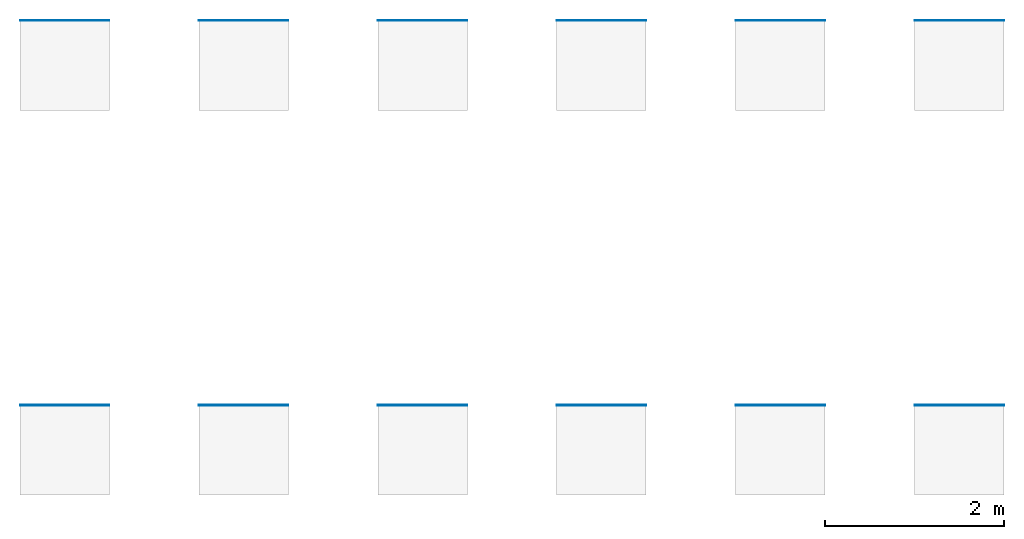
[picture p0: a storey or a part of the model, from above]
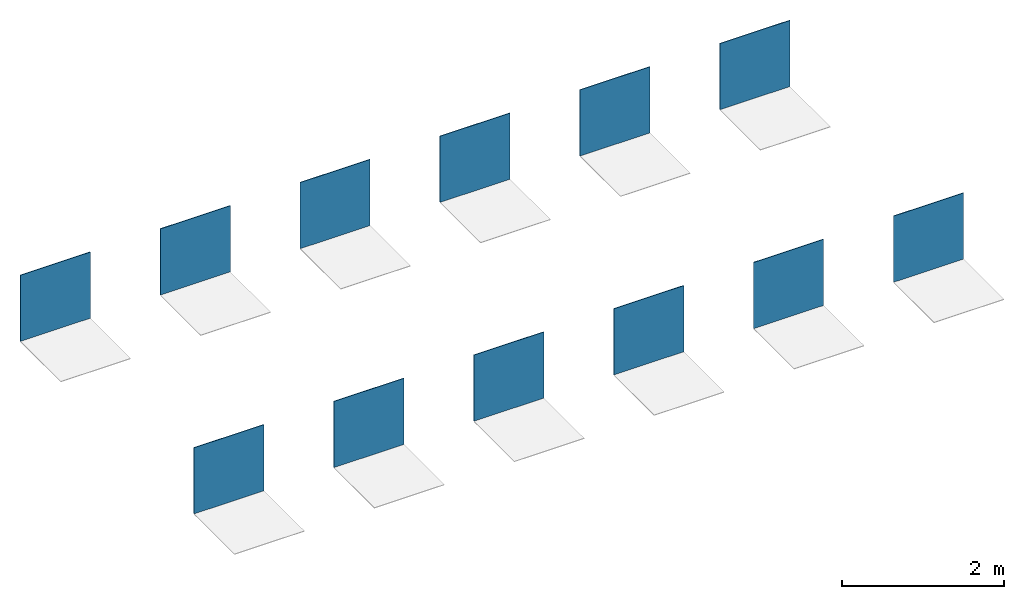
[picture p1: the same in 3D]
Properties of the parts of a building model (IFC2X3), part 1 of 2

# File
Description: ViewDefinition [CoordinationView_V2.0]
Time: 2025-06-20T14:48:58
Written by: The EXPRESS Data Manager Version 5.02.0100.07 : 28 Aug 2013
Made in: 21.1.90.15 - Exporter 21.1.90.15 - Alternate UI 21.1.90.15
Comment: STEP Physical File produced by: The EXPRESS Data Manager Version 5.02.0100.07 : 28 Aug 2013 * Module: EDMstepFileFactory/EDMstandAlone * Creation date: Fri Jun 20 14:48:58 2025 * Host: STB002 * Database: C:\Users\LARISS~1\AppData\Local\Temp\234e31d9-e186-458c-9206-d387dea7a233\5ca75167-f6cb-4baf-9861-9e8454f58231\ifc * Database version: 5507 * Database creation date: Fri Jun 20 14:48:57 2025 * Schema: IFC2X3 * Model: DataRepository.ifc * Model creation date: Fri Jun 20 14:48:57 2025 * Header model: DataRepository.ifc_HeaderModel * Header model creation date: Fri Jun 20 14:48:57 2025 * EDMuser: sdai-user * EDMgroup: sdai-group * License ID and type: 5605 : Permanent license. Expiry date: * EDMstepFileFactory options: 020000

# IfcSite, Default
RefLatitude: 42, 24, 53, 508911; RefLongitude: -71, -15, -29, -58837; RefElevation: 0 mm
Pset_ProductRequirements - Category: Project Information

# IfcBuilding
Pset_BuildingCommon - NumberOfStoreys: 1
Pset_ProductRequirements - Category: Project Information

# IfcBuildingStorey: Level:Level 1, Level 1
LongName: Level 1; Elevation: 0 mm
Pset_AirSideSystemInformation - Name: Level 1
Pset_ProductRequirements - Name: Level 1; Category: Levels

# IfcCovering: Floor:REVIGRÉS-OMNISTONE-HEXAGON-60X60-MATTRECT-BONE, Floor:REVIGRÉS-OMNISTONE-HEXAGON-60X60-MATTRECT-BONE:154203
In: Level 1
Type - PredefinedType: CLADDING; Material: REVIGRÉS-OMNISTONE-HEXAGON-60x60-MATTRECT-BONE 9.8 mm
Type - Pset_CoveringCommon - Reference: 332B13V191; Material: Grés porcelânico
Type - Pset_ElementShading - Roughness: 304.8 mm
Type - Pset_ManufacturerTypeInformation - Manufacturer: REVIGRÉS
Type - Pset_ProductRequirements - Category: Floors
Type - Pset_QuantityTakeOff - Reference: 332B13V191
Type - IFC.REVIGRÉS-Dados do fabricante-Floor Covering - FabricanteURL: https://www.revigres.pt/; ReferenciaModelo: Omnistone; NumeroGlobalDeItemComercial: 332B13V191; Acabamento: MATT RECT; Material: Grés porcelânico; IdentificadorDoOperadorEconomico: 501840856; UrlFabricanteArtigo: https://www.revigres.pt/colecoes/omnistone; PaisOrigem: Portugal
Type - IFC.REVIGRÉS-Dados de desempenho-Floor Covering - Rectilinearidade: ± 0.2% máx.± 0.8 mm; Ortogonalidade: ± 0.2% máx.± 1.5 mm; PlanaridadeDaSuperficie: ± 0.3% máx. ± 1.8 mm; QualidadeDaSuperficie: Cumpre; AbsorcaoDeAgua: < 0.05%; ModuloDeRuptura: > 45 N/mm130; ResistenciaAFlexao: ≥ 3500 N; ResistenciaAAbrasaoProfunda: < 120 mm131; DilatacaoTermicaLinear: ≤ 8,0x10-6 °C-1; ResistenciaAoChoqueTermico: Resiste; DurabilidadeResistenciaAoGeloDegelo: Resiste; ResistenciaAoEscorregamentoDIN51130: R10; ResistenciaAoEscorregamentoDIN51097: B; ResistenciaAoEscorregamentoENV51097: B; ResistenciaAoEscorregamentoENV12633: Class 2; ResistenciaAoEscorregamentoBS7976: >36; ResistenciaAoEscorregamentoANSIA1371: ≥0,42; ResistenciaAoDeslizamentoENV12633: Class 2; ResistenciaAoDeslizamentoBS7976: >36; ResistenciaAsManchas: Class 5; ResistenciaABaixasConcentracoesDeAcidosEAlcalis: Classe LA; ResistenciaAAltasConcentracoesDeAcidosEAlcalis: Classe HA; LibertacaoDeCadmio: 0; LibertacaoDeChumbo: 0
Type - IFC.REVIGRÉS-Dados de especificação-Floor Covering - VariacaoTonalidade: 3; NivelDeTrafego: 5; EPavimento: Sim; ERevestimento: Sim; EExterno: Sim
Type - IFC.REVIGRÉS-Dados geométricos-Floor Covering - AlturaNominal: 9.8 mm; ComprimentoNominal: 59.2 mm; LarguraNominal: 59.2 mm
Type - IFC.REVIGRÉS-Dados de sustentabilidade-Floor Covering - ItemEParcialmenteReciclado: 0; EnergiaTermicaExportada: 0; ItemENovo: Sim; ItemEReciclado: Não; VidaÚtilEsperada: 50; SubstanciasPerigosas: Não; PotencialDeEsgotamentoAbioticoDosRecursosNaoFosseisMineraisEMetais: 0.000701; PotencialDeAquecimentoGlobalBiogenico: -0.48; CombustiveisFosseisComPotencialDeAquecimentoGlobal: 13.9; PotencialDeAquecimentoGlobalUsoDoSoloEMudancaDeUsoDoSolo: 0.0246; PotencialDeEutrofizacaoFraccaoDeNutrientesQueAtingemOCompartimentoFinalDeAguaDoce: 0.000189; PotencialDeEutrofizacaoFraccaoDeNutrientesQueAtingemOCompartimentoFinalMarinho: 0.0122; EnergiaRecuperada: 0.00739; ConsumoDeAguaDoce: 0.113; UtilizacaoLiquidaDeAguaDoce: 0.113; ResiduosPerigososEliminados: 0.00221; ResiduosNaoPerigososEliminados: 1.83; MassaTotalDeResiduosRadioactivosEliminados: 0.000394; EnergiaElectricaExportada: 1.55; MateriaisParaRecuperacaoDeEnergia: 0.00739; MateriaisParaReciclagem: 0.0253; UnidadeEPD: 1 m²
Type - IFC.REVIGRÉS-Dados gerais-Floor Covering - Nome: REVIGRÉS-OMNISTONE-HEXAGON-60X60-MATT RECT-BONE; TipoProduto: Prensado a seco: grupo BIa UGL | Grés porcelânico técnico; NumeroDeRegistoDAP: EPD-REV-20240006-CCC1-EN; ReferenciaDAP: -; UrlDOP: -
Classification: C3020 (Uniformat)
Pset_CoveringCommon - TotalThickness: 9.8 mm
IFC.REVIGRÉS-Dados do fabricante-Floor Covering - Type: Floor: REVIGRÉS-OMNISTONE-HEXAGON-60X60-MATTRECT-BONE
IFC.REVIGRÉS-Dados de desempenho-Floor Covering - Type: Floor: REVIGRÉS-OMNISTONE-HEXAGON-60X60-MATTRECT-BONE
IFC.REVIGRÉS-Dados de especificação-Floor Covering - Type: Floor: REVIGRÉS-OMNISTONE-HEXAGON-60X60-MATTRECT-BONE
IFC.REVIGRÉS-Dados geométricos-Floor Covering - Type: Floor: REVIGRÉS-OMNISTONE-HEXAGON-60X60-MATTRECT-BONE
IFC.REVIGRÉS-Dados de sustentabilidade-Floor Covering - Type: Floor: REVIGRÉS-OMNISTONE-HEXAGON-60X60-MATTRECT-BONE

# IfcCovering: Floor:REVIGRÉS-OMNISTONE-HEXAGON-60X60-MATTRECT-ICE, Floor:REVIGRÉS-OMNISTONE-HEXAGON-60X60-MATTRECT-ICE:154641
In: Level 1
Type - PredefinedType: CLADDING; Material: REVIGRÉS-OMNISTONE-HEXAGON-60x60-MATTRECT-ICE 9.8 mm
Type - Pset_CoveringCommon - Reference: 332B13V201; Material: Grés porcelânico
Type - Pset_ElementShading - Roughness: 304.8 mm
Type - Pset_ManufacturerTypeInformation - Manufacturer: REVIGRÉS
Type - Pset_ProductRequirements - Category: Floors
Type - Pset_QuantityTakeOff - Reference: 332B13V201
Type - IFC.REVIGRÉS-Dados do fabricante-Floor Covering - FabricanteURL: https://www.revigres.pt/; ReferenciaModelo: Omnistone; NumeroGlobalDeItemComercial: 332B13V201; Acabamento: MATT RECT; Material: Grés porcelânico; IdentificadorDoOperadorEconomico: 501840856; UrlFabricanteArtigo: https://www.revigres.pt/colecoes/omnistone; PaisOrigem: Portugal
Type - IFC.REVIGRÉS-Dados de desempenho-Floor Covering - Rectilinearidade: ± 0.2% máx.± 0.8 mm; Ortogonalidade: ± 0.2% máx.± 1.5 mm; PlanaridadeDaSuperficie: ± 0.3% máx. ± 1.8 mm; QualidadeDaSuperficie: Cumpre; AbsorcaoDeAgua: < 0.05%; ModuloDeRuptura: > 45 N/mm130; ResistenciaAFlexao: ≥ 3500 N; ResistenciaAAbrasaoProfunda: < 120 mm131; DilatacaoTermicaLinear: ≤ 8,0x10-6 °C-1; ResistenciaAoChoqueTermico: Resiste; DurabilidadeResistenciaAoGeloDegelo: Resiste; ResistenciaAoEscorregamentoDIN51130: R10; ResistenciaAoEscorregamentoDIN51097: B; ResistenciaAoEscorregamentoENV51097: B; ResistenciaAoEscorregamentoENV12633: Class 2; ResistenciaAoEscorregamentoBS7976: >36; ResistenciaAoEscorregamentoANSIA1371: ≥0,42; ResistenciaAoDeslizamentoENV12633: Class 2; ResistenciaAoDeslizamentoBS7976: >36; ResistenciaAsManchas: Class 5; ResistenciaABaixasConcentracoesDeAcidosEAlcalis: Classe LA; ResistenciaAAltasConcentracoesDeAcidosEAlcalis: Classe HA; LibertacaoDeCadmio: 0; LibertacaoDeChumbo: 0
Type - IFC.REVIGRÉS-Dados de especificação-Floor Covering - VariacaoTonalidade: 3; NivelDeTrafego: 5; EPavimento: Sim; ERevestimento: Sim; EExterno: Sim
Type - IFC.REVIGRÉS-Dados geométricos-Floor Covering - AlturaNominal: 9.8 mm; ComprimentoNominal: 59.2 mm; LarguraNominal: 59.2 mm
Type - IFC.REVIGRÉS-Dados de sustentabilidade-Floor Covering - ItemEParcialmenteReciclado: 0; EnergiaTermicaExportada: 0; ItemENovo: Sim; ItemEReciclado: Não; VidaÚtilEsperada: 50; SubstanciasPerigosas: Não; PotencialDeEsgotamentoAbioticoDosRecursosNaoFosseisMineraisEMetais: 0.000701; PotencialDeAquecimentoGlobalBiogenico: -0.48; CombustiveisFosseisComPotencialDeAquecimentoGlobal: 13.9; PotencialDeAquecimentoGlobalUsoDoSoloEMudancaDeUsoDoSolo: 0.0246; PotencialDeEutrofizacaoFraccaoDeNutrientesQueAtingemOCompartimentoFinalDeAguaDoce: 0.000189; PotencialDeEutrofizacaoFraccaoDeNutrientesQueAtingemOCompartimentoFinalMarinho: 0.0122; EnergiaRecuperada: 0.00739; ConsumoDeAguaDoce: 0.113; UtilizacaoLiquidaDeAguaDoce: 0.113; ResiduosPerigososEliminados: 0.00221; ResiduosNaoPerigososEliminados: 1.83; MassaTotalDeResiduosRadioactivosEliminados: 0.000394; EnergiaElectricaExportada: 1.55; MateriaisParaRecuperacaoDeEnergia: 0.00739; MateriaisParaReciclagem: 0.0253; UnidadeEPD: 1 m²
Type - IFC.REVIGRÉS-Dados gerais-Floor Covering - Nome: REVIGRÉS-OMNISTONE-HEXAGON-60X60-MATT RECT-ICE; TipoProduto: Prensado a seco: grupo BIa UGL | Grés porcelânico técnico; NumeroDeRegistoDAP: EPD-REV-20240006-CCC1-EN; ReferenciaDAP: -; UrlDOP: -
Classification: C3020 (Uniformat)
Pset_CoveringCommon - TotalThickness: 9.8 mm
IFC.REVIGRÉS-Dados do fabricante-Floor Covering - Type: Floor: REVIGRÉS-OMNISTONE-HEXAGON-60X60-MATTRECT-ICE
IFC.REVIGRÉS-Dados de desempenho-Floor Covering - Type: Floor: REVIGRÉS-OMNISTONE-HEXAGON-60X60-MATTRECT-ICE
IFC.REVIGRÉS-Dados de especificação-Floor Covering - Type: Floor: REVIGRÉS-OMNISTONE-HEXAGON-60X60-MATTRECT-ICE
IFC.REVIGRÉS-Dados geométricos-Floor Covering - Type: Floor: REVIGRÉS-OMNISTONE-HEXAGON-60X60-MATTRECT-ICE
IFC.REVIGRÉS-Dados de sustentabilidade-Floor Covering - Type: Floor: REVIGRÉS-OMNISTONE-HEXAGON-60X60-MATTRECT-ICE

# IfcCovering: Floor:REVIGRÉS-OMNISTONE-HEXAGON-60X60-MATTRECT-IRON, Floor:REVIGRÉS-OMNISTONE-HEXAGON-60X60-MATTRECT-IRON:155021
In: Level 1
Type - PredefinedType: CLADDING; Material: REVIGRÉS-OMNISTONE-HEXAGON-60x60-MATTRECT-IRON 9.8 mm
Type - Pset_CoveringCommon - Reference: 332B13V211; Material: Grés porcelânico
Type - Pset_ElementShading - Roughness: 304.8 mm
Type - Pset_ManufacturerTypeInformation - Manufacturer: REVIGRÉS
Type - Pset_ProductRequirements - Category: Floors
Type - Pset_QuantityTakeOff - Reference: 332B13V211
Type - IFC.REVIGRÉS-Dados do fabricante-Floor Covering - FabricanteURL: https://www.revigres.pt/; ReferenciaModelo: Omnistone; NumeroGlobalDeItemComercial: 332B13V211; Acabamento: MATT RECT; Material: Grés porcelânico; IdentificadorDoOperadorEconomico: 501840856; UrlFabricanteArtigo: https://www.revigres.pt/colecoes/omnistone; PaisOrigem: Portugal
Type - IFC.REVIGRÉS-Dados de desempenho-Floor Covering - Rectilinearidade: ± 0.2% máx.± 0.8 mm; Ortogonalidade: ± 0.2% máx.± 1.5 mm; PlanaridadeDaSuperficie: ± 0.3% máx. ± 1.8 mm; QualidadeDaSuperficie: Cumpre; AbsorcaoDeAgua: < 0.05%; ModuloDeRuptura: > 45 N/mm130; ResistenciaAFlexao: ≥ 3500 N; ResistenciaAAbrasaoProfunda: < 120 mm131; DilatacaoTermicaLinear: ≤ 8,0x10-6 °C-1; ResistenciaAoChoqueTermico: Resiste; DurabilidadeResistenciaAoGeloDegelo: Resiste; ResistenciaAoEscorregamentoDIN51130: R10; ResistenciaAoEscorregamentoDIN51097: B; ResistenciaAoEscorregamentoENV51097: B; ResistenciaAoEscorregamentoENV12633: Class 2; ResistenciaAoEscorregamentoBS7976: >36; ResistenciaAoEscorregamentoANSIA1371: ≥0,42; ResistenciaAoDeslizamentoENV12633: Class 2; ResistenciaAoDeslizamentoBS7976: >36; ResistenciaAsManchas: Class 5; ResistenciaABaixasConcentracoesDeAcidosEAlcalis: Classe LA; ResistenciaAAltasConcentracoesDeAcidosEAlcalis: Classe HA; LibertacaoDeCadmio: 0; LibertacaoDeChumbo: 0
Type - IFC.REVIGRÉS-Dados de especificação-Floor Covering - VariacaoTonalidade: 3; NivelDeTrafego: 5; EPavimento: Sim; ERevestimento: Sim; EExterno: Sim
Type - IFC.REVIGRÉS-Dados geométricos-Floor Covering - AlturaNominal: 9.8 mm; ComprimentoNominal: 59.2 mm; LarguraNominal: 59.2 mm
Type - IFC.REVIGRÉS-Dados de sustentabilidade-Floor Covering - EnergiaTermicaExportada: 0; ItemENovo: Sim; ItemEParcialmenteReciclado: 0.14; ItemEReciclado: Sim; VidaÚtilEsperada: 50; SubstanciasPerigosas: Não; PotencialDeEsgotamentoAbioticoDosRecursosNaoFosseisMineraisEMetais: 0.000701; PotencialDeAquecimentoGlobalBiogenico: -0.48; CombustiveisFosseisComPotencialDeAquecimentoGlobal: 13.9; PotencialDeAquecimentoGlobalUsoDoSoloEMudancaDeUsoDoSolo: 0.0246; PotencialDeEutrofizacaoFraccaoDeNutrientesQueAtingemOCompartimentoFinalDeAguaDoce: 0.000189; PotencialDeEutrofizacaoFraccaoDeNutrientesQueAtingemOCompartimentoFinalMarinho: 0.0122; EnergiaRecuperada: 0.00739; ConsumoDeAguaDoce: 0.113; UtilizacaoLiquidaDeAguaDoce: 0.113; ResiduosPerigososEliminados: 0.00221; ResiduosNaoPerigososEliminados: 1.83; MassaTotalDeResiduosRadioactivosEliminados: 0.000394; EnergiaElectricaExportada: 1.55; MateriaisParaRecuperacaoDeEnergia: 0.00739; MateriaisParaReciclagem: 0.0253; UnidadeEPD: 1 m²
Type - IFC.REVIGRÉS-Dados gerais-Floor Covering - Nome: REVIGRÉS-OMNISTONE-HEXAGON-60X60-MATT RECT-IRON; TipoProduto: Prensado a seco: grupo BIa UGL | Grés porcelânico técnico; NumeroDeRegistoDAP: EPD-REV-20240006-CCC1-EN; ReferenciaDAP: -; UrlDOP: -
Classification: C3020 (Uniformat)
Pset_CoveringCommon - TotalThickness: 9.8 mm
IFC.REVIGRÉS-Dados do fabricante-Floor Covering - Type: Floor: REVIGRÉS-OMNISTONE-HEXAGON-60X60-MATTRECT-IRON
IFC.REVIGRÉS-Dados de desempenho-Floor Covering - Type: Floor: REVIGRÉS-OMNISTONE-HEXAGON-60X60-MATTRECT-IRON
IFC.REVIGRÉS-Dados de especificação-Floor Covering - Type: Floor: REVIGRÉS-OMNISTONE-HEXAGON-60X60-MATTRECT-IRON
IFC.REVIGRÉS-Dados geométricos-Floor Covering - Type: Floor: REVIGRÉS-OMNISTONE-HEXAGON-60X60-MATTRECT-IRON
IFC.REVIGRÉS-Dados de sustentabilidade-Floor Covering - Type: Floor: REVIGRÉS-OMNISTONE-HEXAGON-60X60-MATTRECT-IRON

# IfcCovering: Floor:REVIGRÉS-OMNISTONE-HEXAGON-60X60-MATTRECT-JET, Floor:REVIGRÉS-OMNISTONE-HEXAGON-60X60-MATTRECT-JET:155129
In: Level 1
Type - PredefinedType: CLADDING; Material: REVIGRÉS-OMNISTONE-HEXAGON-60x60-MATTRECT-JET 9.8 mm
Type - Pset_CoveringCommon - Reference: 332B13V221; Material: Grés porcelânico
Type - Pset_ElementShading - Roughness: 304.8 mm
Type - Pset_ManufacturerTypeInformation - Manufacturer: REVIGRÉS
Type - Pset_ProductRequirements - Category: Floors
Type - Pset_QuantityTakeOff - Reference: 332B13V221
Type - IFC.REVIGRÉS-Dados do fabricante-Floor Covering - FabricanteURL: https://www.revigres.pt/; ReferenciaModelo: Omnistone; NumeroGlobalDeItemComercial: 332B13V221; Acabamento: MATT RECT; Material: Grés porcelânico; IdentificadorDoOperadorEconomico: 501840856; UrlFabricanteArtigo: https://www.revigres.pt/colecoes/omnistone; PaisOrigem: Portugal
Type - IFC.REVIGRÉS-Dados de desempenho-Floor Covering - Rectilinearidade: ± 0.2% máx.± 0.8 mm; Ortogonalidade: ± 0.2% máx.± 1.5 mm; PlanaridadeDaSuperficie: ± 0.3% máx. ± 1.8 mm; QualidadeDaSuperficie: Cumpre; AbsorcaoDeAgua: < 0.05%; ModuloDeRuptura: > 45 N/mm130; ResistenciaAFlexao: ≥ 3500 N; ResistenciaAAbrasaoProfunda: < 120 mm131; DilatacaoTermicaLinear: ≤ 8,0x10-6 °C-1; ResistenciaAoChoqueTermico: Resiste; DurabilidadeResistenciaAoGeloDegelo: Resiste; ResistenciaAoEscorregamentoDIN51130: R10; ResistenciaAoEscorregamentoDIN51097: B; ResistenciaAoEscorregamentoENV51097: B; ResistenciaAoEscorregamentoENV12633: Class 2; ResistenciaAoEscorregamentoBS7976: >36; ResistenciaAoEscorregamentoANSIA1371: ≥0,42; ResistenciaAoDeslizamentoENV12633: Class 2; ResistenciaAoDeslizamentoBS7976: >36; ResistenciaAsManchas: Class 5; ResistenciaABaixasConcentracoesDeAcidosEAlcalis: Classe LA; ResistenciaAAltasConcentracoesDeAcidosEAlcalis: Classe HA; LibertacaoDeCadmio: 0; LibertacaoDeChumbo: 0
Type - IFC.REVIGRÉS-Dados de especificação-Floor Covering - VariacaoTonalidade: 3; NivelDeTrafego: 5; EPavimento: Sim; ERevestimento: Sim; EExterno: Sim
Type - IFC.REVIGRÉS-Dados geométricos-Floor Covering - AlturaNominal: 9.8 mm; ComprimentoNominal: 59.2 mm; LarguraNominal: 59.2 mm
Type - IFC.REVIGRÉS-Dados de sustentabilidade-Floor Covering - ItemEParcialmenteReciclado: 0; EnergiaTermicaExportada: 0; ItemENovo: Sim; ItemEReciclado: Não; VidaÚtilEsperada: 50; SubstanciasPerigosas: Não; PotencialDeEsgotamentoAbioticoDosRecursosNaoFosseisMineraisEMetais: 0.000701; PotencialDeAquecimentoGlobalBiogenico: -0.48; CombustiveisFosseisComPotencialDeAquecimentoGlobal: 13.9; PotencialDeAquecimentoGlobalUsoDoSoloEMudancaDeUsoDoSolo: 0.0246; PotencialDeEutrofizacaoFraccaoDeNutrientesQueAtingemOCompartimentoFinalDeAguaDoce: 0.000189; PotencialDeEutrofizacaoFraccaoDeNutrientesQueAtingemOCompartimentoFinalMarinho: 0.0122; EnergiaRecuperada: 0.00739; ConsumoDeAguaDoce: 0.113; UtilizacaoLiquidaDeAguaDoce: 0.113; ResiduosPerigososEliminados: 0.00221; ResiduosNaoPerigososEliminados: 1.83; MassaTotalDeResiduosRadioactivosEliminados: 0.000394; EnergiaElectricaExportada: 1.55; MateriaisParaRecuperacaoDeEnergia: 0.00739; MateriaisParaReciclagem: 0.0253; UnidadeEPD: 1 m²
Type - IFC.REVIGRÉS-Dados gerais-Floor Covering - Nome: REVIGRÉS-OMNISTONE-HEXAGON-60X60-MATT RECT-JET; TipoProduto: Prensado a seco: grupo BIa UGL | Grés porcelânico técnico; NumeroDeRegistoDAP: EPD-REV-20240006-CCC1-EN; ReferenciaDAP: -; UrlDOP: -
Classification: C3020 (Uniformat)
Pset_CoveringCommon - TotalThickness: 9.8 mm
IFC.REVIGRÉS-Dados do fabricante-Floor Covering - Type: Floor: REVIGRÉS-OMNISTONE-HEXAGON-60X60-MATTRECT-JET
IFC.REVIGRÉS-Dados de desempenho-Floor Covering - Type: Floor: REVIGRÉS-OMNISTONE-HEXAGON-60X60-MATTRECT-JET
IFC.REVIGRÉS-Dados de especificação-Floor Covering - Type: Floor: REVIGRÉS-OMNISTONE-HEXAGON-60X60-MATTRECT-JET
IFC.REVIGRÉS-Dados geométricos-Floor Covering - Type: Floor: REVIGRÉS-OMNISTONE-HEXAGON-60X60-MATTRECT-JET
IFC.REVIGRÉS-Dados de sustentabilidade-Floor Covering - Type: Floor: REVIGRÉS-OMNISTONE-HEXAGON-60X60-MATTRECT-JET

# IfcCovering: Floor:REVIGRÉS-OMNISTONE-HEXAGON-60X60-MATTRECT-PLATINA, Floor:REVIGRÉS-OMNISTONE-HEXAGON-60X60-MATTRECT-PLATINA:155236
In: Level 1
Type - PredefinedType: CLADDING; Material: REVIGRÉS-OMNISTONE-HEXAGON-60x60-MATTRECT-PLATINA 9.8 mm
Type - Pset_CoveringCommon - Reference: 332B13V231; Material: Grés porcelânico
Type - Pset_ElementShading - Roughness: 304.8 mm
Type - Pset_ManufacturerTypeInformation - Manufacturer: REVIGRÉS
Type - Pset_ProductRequirements - Category: Floors
Type - Pset_QuantityTakeOff - Reference: 332B13V231
Type - IFC.REVIGRÉS-Dados do fabricante-Floor Covering - FabricanteURL: https://www.revigres.pt/; ReferenciaModelo: Omnistone; NumeroGlobalDeItemComercial: 332B13V231; Acabamento: MATT RECT; Material: Grés porcelânico; IdentificadorDoOperadorEconomico: 501840856; UrlFabricanteArtigo: https://www.revigres.pt/colecoes/omnistone; PaisOrigem: Portugal
Type - IFC.REVIGRÉS-Dados de desempenho-Floor Covering - Rectilinearidade: ± 0.2% máx.± 0.8 mm; Ortogonalidade: ± 0.2% máx.± 1.5 mm; PlanaridadeDaSuperficie: ± 0.3% máx. ± 1.8 mm; QualidadeDaSuperficie: Cumpre; AbsorcaoDeAgua: < 0.05%; ModuloDeRuptura: > 45 N/mm130; ResistenciaAFlexao: ≥ 3500 N; ResistenciaAAbrasaoProfunda: < 120 mm131; DilatacaoTermicaLinear: ≤ 8,0x10-6 °C-1; ResistenciaAoChoqueTermico: Resiste; DurabilidadeResistenciaAoGeloDegelo: Resiste; ResistenciaAoEscorregamentoDIN51130: R10; ResistenciaAoEscorregamentoDIN51097: B; ResistenciaAoEscorregamentoENV51097: B; ResistenciaAoEscorregamentoENV12633: Class 2; ResistenciaAoEscorregamentoBS7976: >36; ResistenciaAoEscorregamentoANSIA1371: ≥0,42; ResistenciaAoDeslizamentoENV12633: Class 2; ResistenciaAoDeslizamentoBS7976: >36; ResistenciaAsManchas: Class 5; ResistenciaABaixasConcentracoesDeAcidosEAlcalis: Classe LA; ResistenciaAAltasConcentracoesDeAcidosEAlcalis: Classe HA; LibertacaoDeCadmio: 0; LibertacaoDeChumbo: 0
Type - IFC.REVIGRÉS-Dados de especificação-Floor Covering - VariacaoTonalidade: 3; NivelDeTrafego: 5; EPavimento: Sim; ERevestimento: Sim; EExterno: Sim
Type - IFC.REVIGRÉS-Dados geométricos-Floor Covering - AlturaNominal: 9.8 mm; ComprimentoNominal: 59.2 mm; LarguraNominal: 59.2 mm
Type - IFC.REVIGRÉS-Dados de sustentabilidade-Floor Covering - ItemEParcialmenteReciclado: 0; EnergiaTermicaExportada: 0; ItemENovo: Sim; ItemEReciclado: Não; VidaÚtilEsperada: 50; SubstanciasPerigosas: Não; PotencialDeEsgotamentoAbioticoDosRecursosNaoFosseisMineraisEMetais: 0.000701; PotencialDeAquecimentoGlobalBiogenico: -0.48; CombustiveisFosseisComPotencialDeAquecimentoGlobal: 13.9; PotencialDeAquecimentoGlobalUsoDoSoloEMudancaDeUsoDoSolo: 0.0246; PotencialDeEutrofizacaoFraccaoDeNutrientesQueAtingemOCompartimentoFinalDeAguaDoce: 0.000189; PotencialDeEutrofizacaoFraccaoDeNutrientesQueAtingemOCompartimentoFinalMarinho: 0.0122; EnergiaRecuperada: 0.00739; ConsumoDeAguaDoce: 0.113; UtilizacaoLiquidaDeAguaDoce: 0.113; ResiduosPerigososEliminados: 0.00221; ResiduosNaoPerigososEliminados: 1.83; MassaTotalDeResiduosRadioactivosEliminados: 0.000394; EnergiaElectricaExportada: 1.55; MateriaisParaRecuperacaoDeEnergia: 0.00739; MateriaisParaReciclagem: 0.0253; UnidadeEPD: 1 m²
Type - IFC.REVIGRÉS-Dados gerais-Floor Covering - Nome: REVIGRÉS-OMNISTONE-HEXAGON-60X60-MATT RECT-PLATINA; TipoProduto: Prensado a seco: grupo BIa UGL | Grés porcelânico técnico; NumeroDeRegistoDAP: EPD-REV-20240006-CCC1-EN; ReferenciaDAP: -; UrlDOP: -
Classification: C3020 (Uniformat)
Pset_CoveringCommon - TotalThickness: 9.8 mm
IFC.REVIGRÉS-Dados do fabricante-Floor Covering - Type: Floor: REVIGRÉS-OMNISTONE-HEXAGON-60X60-MATTRECT-PLATINA
IFC.REVIGRÉS-Dados de desempenho-Floor Covering - Type: Floor: REVIGRÉS-OMNISTONE-HEXAGON-60X60-MATTRECT-PLATINA
IFC.REVIGRÉS-Dados de especificação-Floor Covering - Type: Floor: REVIGRÉS-OMNISTONE-HEXAGON-60X60-MATTRECT-PLATINA
IFC.REVIGRÉS-Dados geométricos-Floor Covering - Type: Floor: REVIGRÉS-OMNISTONE-HEXAGON-60X60-MATTRECT-PLATINA
IFC.REVIGRÉS-Dados de sustentabilidade-Floor Covering - Type: Floor: REVIGRÉS-OMNISTONE-HEXAGON-60X60-MATTRECT-PLATINA

# IfcCovering: Floor:REVIGRÉS-OMNISTONE-HEXAGON-60X60-MATTRECT-ROPE, Floor:REVIGRÉS-OMNISTONE-HEXAGON-60X60-MATTRECT-ROPE:155358
In: Level 1
Type - PredefinedType: CLADDING; Material: REVIGRÉS-OMNISTONE-HEXAGON-60x60-MATTRECT-ROPE 9.8 mm
Type - Pset_CoveringCommon - Reference: 332B13V241; Material: Grés porcelânico
Type - Pset_ElementShading - Roughness: 304.8 mm
Type - Pset_ManufacturerTypeInformation - Manufacturer: REVIGRÉS
Type - Pset_ProductRequirements - Category: Floors
Type - Pset_QuantityTakeOff - Reference: 332B13V241
Type - IFC.REVIGRÉS-Dados do fabricante-Floor Covering - FabricanteURL: https://www.revigres.pt/; ReferenciaModelo: Omnistone; NumeroGlobalDeItemComercial: 332B13V241; Acabamento: MATT RECT; Material: Grés porcelânico; IdentificadorDoOperadorEconomico: 501840856; UrlFabricanteArtigo: https://www.revigres.pt/colecoes/omnistone; PaisOrigem: Portugal
Type - IFC.REVIGRÉS-Dados de desempenho-Floor Covering - Rectilinearidade: ± 0.2% máx.± 0.8 mm; Ortogonalidade: ± 0.2% máx.± 1.5 mm; PlanaridadeDaSuperficie: ± 0.3% máx. ± 1.8 mm; QualidadeDaSuperficie: Cumpre; AbsorcaoDeAgua: < 0.05%; ModuloDeRuptura: > 45 N/mm130; ResistenciaAFlexao: ≥ 3500 N; ResistenciaAAbrasaoProfunda: < 120 mm131; DilatacaoTermicaLinear: ≤ 8,0x10-6 °C-1; ResistenciaAoChoqueTermico: Resiste; DurabilidadeResistenciaAoGeloDegelo: Resiste; ResistenciaAoEscorregamentoDIN51130: R10; ResistenciaAoEscorregamentoDIN51097: B; ResistenciaAoEscorregamentoENV51097: B; ResistenciaAoEscorregamentoENV12633: Class 2; ResistenciaAoEscorregamentoBS7976: >36; ResistenciaAoEscorregamentoANSIA1371: ≥0,42; ResistenciaAoDeslizamentoENV12633: Class 2; ResistenciaAoDeslizamentoBS7976: >36; ResistenciaAsManchas: Class 5; ResistenciaABaixasConcentracoesDeAcidosEAlcalis: Classe LA; ResistenciaAAltasConcentracoesDeAcidosEAlcalis: Classe HA; LibertacaoDeCadmio: 0; LibertacaoDeChumbo: 0
Type - IFC.REVIGRÉS-Dados de especificação-Floor Covering - VariacaoTonalidade: 3; NivelDeTrafego: 5; EPavimento: Sim; ERevestimento: Sim; EExterno: Sim
Type - IFC.REVIGRÉS-Dados geométricos-Floor Covering - AlturaNominal: 9.8 mm; ComprimentoNominal: 59.2 mm; LarguraNominal: 59.2 mm
Type - IFC.REVIGRÉS-Dados de sustentabilidade-Floor Covering - ItemEParcialmenteReciclado: 0; EnergiaTermicaExportada: 0; ItemENovo: Sim; ItemEReciclado: Não; VidaÚtilEsperada: 50; SubstanciasPerigosas: Não; PotencialDeEsgotamentoAbioticoDosRecursosNaoFosseisMineraisEMetais: 0.000701; PotencialDeAquecimentoGlobalBiogenico: -0.48; CombustiveisFosseisComPotencialDeAquecimentoGlobal: 13.9; PotencialDeAquecimentoGlobalUsoDoSoloEMudancaDeUsoDoSolo: 0.0246; PotencialDeEutrofizacaoFraccaoDeNutrientesQueAtingemOCompartimentoFinalDeAguaDoce: 0.000189; PotencialDeEutrofizacaoFraccaoDeNutrientesQueAtingemOCompartimentoFinalMarinho: 0.0122; EnergiaRecuperada: 0.00739; ConsumoDeAguaDoce: 0.113; UtilizacaoLiquidaDeAguaDoce: 0.113; ResiduosPerigososEliminados: 0.00221; ResiduosNaoPerigososEliminados: 1.83; MassaTotalDeResiduosRadioactivosEliminados: 0.000394; EnergiaElectricaExportada: 1.55; MateriaisParaRecuperacaoDeEnergia: 0.00739; MateriaisParaReciclagem: 0.0253; UnidadeEPD: 1 m²
Type - IFC.REVIGRÉS-Dados gerais-Floor Covering - Nome: REVIGRÉS-OMNISTONE-HEXAGON-60X60-MATT RECT-ROPE; TipoProduto: Prensado a seco: grupo BIa UGL | Grés porcelânico técnico; NumeroDeRegistoDAP: EPD-REV-20240006-CCC1-EN; ReferenciaDAP: -; UrlDOP: -
Classification: C3020 (Uniformat)
Pset_CoveringCommon - TotalThickness: 9.8 mm
IFC.REVIGRÉS-Dados do fabricante-Floor Covering - Type: Floor: REVIGRÉS-OMNISTONE-HEXAGON-60X60-MATTRECT-ROPE
IFC.REVIGRÉS-Dados de desempenho-Floor Covering - Type: Floor: REVIGRÉS-OMNISTONE-HEXAGON-60X60-MATTRECT-ROPE
IFC.REVIGRÉS-Dados de especificação-Floor Covering - Type: Floor: REVIGRÉS-OMNISTONE-HEXAGON-60X60-MATTRECT-ROPE
IFC.REVIGRÉS-Dados geométricos-Floor Covering - Type: Floor: REVIGRÉS-OMNISTONE-HEXAGON-60X60-MATTRECT-ROPE
IFC.REVIGRÉS-Dados de sustentabilidade-Floor Covering - Type: Floor: REVIGRÉS-OMNISTONE-HEXAGON-60X60-MATTRECT-ROPE

# IfcCovering: Floor:REVIGRÉS-OMNISTONE-HEXAGON-60X60-SOFT-BONE, Floor:REVIGRÉS-OMNISTONE-HEXAGON-60X60-SOFT-BONE:154273
In: Level 1
Type - PredefinedType: CLADDING; Material: REVIGRÉS-OMNISTONE-HEXAGON-60x60-SOFT-BONE 9.8 mm
Type - Pset_CoveringCommon - Reference: 332613V191; Material: Grés porcelânico
Type - Pset_ElementShading - Roughness: 304.8 mm
Type - Pset_ManufacturerTypeInformation - Manufacturer: REVIGRÉS
Type - Pset_ProductRequirements - Category: Floors
Type - Pset_QuantityTakeOff - Reference: 332613V191
Type - IFC.REVIGRÉS-Dados do fabricante-Floor Covering - FabricanteURL: https://www.revigres.pt/; ReferenciaModelo: Omnistone; NumeroGlobalDeItemComercial: 332613V191; Acabamento: SOFT; Material: Grés porcelânico; IdentificadorDoOperadorEconomico: 501840856; UrlFabricanteArtigo: https://www.revigres.pt/colecoes/omnistone; PaisOrigem: Portugal
Type - IFC.REVIGRÉS-Dados de desempenho-Floor Covering - Rectilinearidade: ± 0.2% máx.± 0.8 mm; Ortogonalidade: ± 0.2% máx.± 1.5 mm; PlanaridadeDaSuperficie: ± 0.3% máx. ± 1.8 mm; QualidadeDaSuperficie: Cumpre; AbsorcaoDeAgua: < 0.05%; ModuloDeRuptura: > 45 N/mm130; ResistenciaAFlexao: ≥ 3500 N; ResistenciaAAbrasaoProfunda: < 120 mm131; DilatacaoTermicaLinear: ≤ 8,0x10-6 °C-1; ResistenciaAoChoqueTermico: Resiste; DurabilidadeResistenciaAoGeloDegelo: Resiste; ResistenciaAsManchas: Class 5; ResistenciaABaixasConcentracoesDeAcidosEAlcalis: Classe LA; ResistenciaAAltasConcentracoesDeAcidosEAlcalis: Classe HA; LibertacaoDeCadmio: 0; LibertacaoDeChumbo: 0
Type - IFC.REVIGRÉS-Dados de especificação-Floor Covering - VariacaoTonalidade: 3; NivelDeTrafego: 5; EPavimento: Sim; ERevestimento: Sim; EExterno: Sim
Type - IFC.REVIGRÉS-Dados geométricos-Floor Covering - AlturaNominal: 9.8 mm; ComprimentoNominal: 59.2 mm; LarguraNominal: 59.2 mm
Type - IFC.REVIGRÉS-Dados de sustentabilidade-Floor Covering - ItemEParcialmenteReciclado: 0; EnergiaTermicaExportada: 0; ItemENovo: Sim; ItemEReciclado: Não; VidaÚtilEsperada: 50; SubstanciasPerigosas: Não; PotencialDeEsgotamentoAbioticoDosRecursosNaoFosseisMineraisEMetais: 0.000701; PotencialDeAquecimentoGlobalBiogenico: -0.48; CombustiveisFosseisComPotencialDeAquecimentoGlobal: 13.9; PotencialDeAquecimentoGlobalUsoDoSoloEMudancaDeUsoDoSolo: 0.0246; PotencialDeEutrofizacaoFraccaoDeNutrientesQueAtingemOCompartimentoFinalDeAguaDoce: 0.000189; PotencialDeEutrofizacaoFraccaoDeNutrientesQueAtingemOCompartimentoFinalMarinho: 0.0122; EnergiaRecuperada: 0.00739; ConsumoDeAguaDoce: 0.113; UtilizacaoLiquidaDeAguaDoce: 0.113; ResiduosPerigososEliminados: 0.00221; ResiduosNaoPerigososEliminados: 1.83; MassaTotalDeResiduosRadioactivosEliminados: 0.000394; EnergiaElectricaExportada: 1.55; MateriaisParaRecuperacaoDeEnergia: 0.00739; MateriaisParaReciclagem: 0.0253; UnidadeEPD: 1 m²
Type - IFC.REVIGRÉS-Dados gerais-Floor Covering - Nome: REVIGRÉS-OMNISTONE-HEXAGON-60X60-SOFT-BONE; TipoProduto: Prensado a seco: grupo BIa UGL | Grés porcelânico técnico; NumeroDeRegistoDAP: EPD-REV-20240006-CCC1-EN; ReferenciaDAP: -; UrlDOP: -
Classification: C3020 (Uniformat)
Pset_CoveringCommon - TotalThickness: 9.8 mm
IFC.REVIGRÉS-Dados do fabricante-Floor Covering - Type: Floor: REVIGRÉS-OMNISTONE-HEXAGON-60X60-SOFT-BONE
IFC.REVIGRÉS-Dados de desempenho-Floor Covering - Type: Floor: REVIGRÉS-OMNISTONE-HEXAGON-60X60-SOFT-BONE
IFC.REVIGRÉS-Dados de especificação-Floor Covering - Type: Floor: REVIGRÉS-OMNISTONE-HEXAGON-60X60-SOFT-BONE
IFC.REVIGRÉS-Dados geométricos-Floor Covering - Type: Floor: REVIGRÉS-OMNISTONE-HEXAGON-60X60-SOFT-BONE
IFC.REVIGRÉS-Dados de sustentabilidade-Floor Covering - Type: Floor: REVIGRÉS-OMNISTONE-HEXAGON-60X60-SOFT-BONE

# IfcCovering: Floor:REVIGRÉS-OMNISTONE-HEXAGON-60X60-SOFT-ICE, Floor:REVIGRÉS-OMNISTONE-HEXAGON-60X60-SOFT-ICE:154648
In: Level 1
Type - PredefinedType: CLADDING; Material: REVIGRÉS-OMNISTONE-HEXAGON-60x60-SOFT-ICE 9.8 mm
Type - Pset_CoveringCommon - Reference: 332613V201; Material: Grés porcelânico
Type - Pset_ElementShading - Roughness: 304.8 mm
Type - Pset_ManufacturerTypeInformation - Manufacturer: REVIGRÉS
Type - Pset_ProductRequirements - Category: Floors
Type - Pset_QuantityTakeOff - Reference: 332613V201
Type - IFC.REVIGRÉS-Dados do fabricante-Floor Covering - FabricanteURL: https://www.revigres.pt/; ReferenciaModelo: Omnistone; NumeroGlobalDeItemComercial: 332613V201; Acabamento: SOFT; Material: Grés porcelânico; IdentificadorDoOperadorEconomico: 501840856; UrlFabricanteArtigo: https://www.revigres.pt/colecoes/omnistone; PaisOrigem: Portugal
Type - IFC.REVIGRÉS-Dados de desempenho-Floor Covering - Rectilinearidade: ± 0.2% máx.± 0.8 mm; Ortogonalidade: ± 0.2% máx.± 1.5 mm; PlanaridadeDaSuperficie: ± 0.3% máx. ± 1.8 mm; QualidadeDaSuperficie: Cumpre; AbsorcaoDeAgua: < 0.05%; ModuloDeRuptura: > 45 N/mm130; ResistenciaAFlexao: ≥ 3500 N; ResistenciaAAbrasaoProfunda: < 120 mm131; DilatacaoTermicaLinear: ≤ 8,0x10-6 °C-1; ResistenciaAoChoqueTermico: Resiste; DurabilidadeResistenciaAoGeloDegelo: Resiste; ResistenciaAsManchas: Class 5; ResistenciaABaixasConcentracoesDeAcidosEAlcalis: Classe LA; ResistenciaAAltasConcentracoesDeAcidosEAlcalis: Classe HA; LibertacaoDeCadmio: 0; LibertacaoDeChumbo: 0
Type - IFC.REVIGRÉS-Dados de especificação-Floor Covering - VariacaoTonalidade: 3; NivelDeTrafego: 5; EPavimento: Sim; ERevestimento: Sim; EExterno: Sim
Type - IFC.REVIGRÉS-Dados geométricos-Floor Covering - AlturaNominal: 9.8 mm; ComprimentoNominal: 59.2 mm; LarguraNominal: 59.2 mm
Type - IFC.REVIGRÉS-Dados de sustentabilidade-Floor Covering - ItemEParcialmenteReciclado: 0; EnergiaTermicaExportada: 0; ItemENovo: Sim; ItemEReciclado: Não; VidaÚtilEsperada: 50; SubstanciasPerigosas: Não; PotencialDeEsgotamentoAbioticoDosRecursosNaoFosseisMineraisEMetais: 0.000701; PotencialDeAquecimentoGlobalBiogenico: -0.48; CombustiveisFosseisComPotencialDeAquecimentoGlobal: 13.9; PotencialDeAquecimentoGlobalUsoDoSoloEMudancaDeUsoDoSolo: 0.0246; PotencialDeEutrofizacaoFraccaoDeNutrientesQueAtingemOCompartimentoFinalDeAguaDoce: 0.000189; PotencialDeEutrofizacaoFraccaoDeNutrientesQueAtingemOCompartimentoFinalMarinho: 0.0122; EnergiaRecuperada: 0.00739; ConsumoDeAguaDoce: 0.113; UtilizacaoLiquidaDeAguaDoce: 0.113; ResiduosPerigososEliminados: 0.00221; ResiduosNaoPerigososEliminados: 1.83; MassaTotalDeResiduosRadioactivosEliminados: 0.000394; EnergiaElectricaExportada: 1.55; MateriaisParaRecuperacaoDeEnergia: 0.00739; MateriaisParaReciclagem: 0.0253; UnidadeEPD: 1 m²
Type - IFC.REVIGRÉS-Dados gerais-Floor Covering - Nome: REVIGRÉS-OMNISTONE-HEXAGON-60X60-SOFT-ICE; TipoProduto: Prensado a seco: grupo BIa UGL | Grés porcelânico técnico; NumeroDeRegistoDAP: EPD-REV-20240006-CCC1-EN; ReferenciaDAP: -; UrlDOP: -
Classification: C3020 (Uniformat)
Pset_CoveringCommon - TotalThickness: 9.8 mm
IFC.REVIGRÉS-Dados do fabricante-Floor Covering - Type: Floor: REVIGRÉS-OMNISTONE-HEXAGON-60X60-SOFT-ICE
IFC.REVIGRÉS-Dados de desempenho-Floor Covering - Type: Floor: REVIGRÉS-OMNISTONE-HEXAGON-60X60-SOFT-ICE
IFC.REVIGRÉS-Dados de especificação-Floor Covering - Type: Floor: REVIGRÉS-OMNISTONE-HEXAGON-60X60-SOFT-ICE
IFC.REVIGRÉS-Dados geométricos-Floor Covering - Type: Floor: REVIGRÉS-OMNISTONE-HEXAGON-60X60-SOFT-ICE
IFC.REVIGRÉS-Dados de sustentabilidade-Floor Covering - Type: Floor: REVIGRÉS-OMNISTONE-HEXAGON-60X60-SOFT-ICE

# IfcCovering: Floor:REVIGRÉS-OMNISTONE-HEXAGON-60X60-SOFT-IRON, Floor:REVIGRÉS-OMNISTONE-HEXAGON-60X60-SOFT-IRON:155028
In: Level 1
Type - PredefinedType: CLADDING; Material: REVIGRÉS-OMNISTONE-HEXAGON-60x60-SOFT-IRON 9.8 mm
Type - Pset_CoveringCommon - Reference: 332613V211; Material: Grés porcelânico
Type - Pset_ElementShading - Roughness: 304.8 mm
Type - Pset_ManufacturerTypeInformation - Manufacturer: REVIGRÉS
Type - Pset_ProductRequirements - Category: Floors
Type - Pset_QuantityTakeOff - Reference: 332613V211
Type - IFC.REVIGRÉS-Dados do fabricante-Floor Covering - FabricanteURL: https://www.revigres.pt/; ReferenciaModelo: Omnistone; NumeroGlobalDeItemComercial: 332613V211; Acabamento: SOFT; Material: Grés porcelânico; IdentificadorDoOperadorEconomico: 501840856; UrlFabricanteArtigo: https://www.revigres.pt/colecoes/omnistone; PaisOrigem: Portugal
Type - IFC.REVIGRÉS-Dados de desempenho-Floor Covering - Rectilinearidade: ± 0.2% máx.± 0.8 mm; Ortogonalidade: ± 0.2% máx.± 1.5 mm; PlanaridadeDaSuperficie: ± 0.3% máx. ± 1.8 mm; QualidadeDaSuperficie: Cumpre; AbsorcaoDeAgua: < 0.05%; ModuloDeRuptura: > 45 N/mm130; ResistenciaAFlexao: ≥ 3500 N; ResistenciaAAbrasaoProfunda: < 120 mm131; DilatacaoTermicaLinear: ≤ 8,0x10-6 °C-1; ResistenciaAoChoqueTermico: Resiste; DurabilidadeResistenciaAoGeloDegelo: Resiste; ResistenciaAsManchas: Class 5; ResistenciaABaixasConcentracoesDeAcidosEAlcalis: Classe LA; ResistenciaAAltasConcentracoesDeAcidosEAlcalis: Classe HA; LibertacaoDeCadmio: 0; LibertacaoDeChumbo: 0
Type - IFC.REVIGRÉS-Dados de especificação-Floor Covering - VariacaoTonalidade: 3; NivelDeTrafego: 5; EPavimento: Sim; ERevestimento: Sim; EExterno: Sim
Type - IFC.REVIGRÉS-Dados geométricos-Floor Covering - AlturaNominal: 9.8 mm; ComprimentoNominal: 59.2 mm; LarguraNominal: 59.2 mm
Type - IFC.REVIGRÉS-Dados de sustentabilidade-Floor Covering - EnergiaTermicaExportada: 0; ItemENovo: Sim; ItemEParcialmenteReciclado: 0.14; ItemEReciclado: Sim; VidaÚtilEsperada: 50; SubstanciasPerigosas: Não; PotencialDeEsgotamentoAbioticoDosRecursosNaoFosseisMineraisEMetais: 0.000701; PotencialDeAquecimentoGlobalBiogenico: -0.48; CombustiveisFosseisComPotencialDeAquecimentoGlobal: 13.9; PotencialDeAquecimentoGlobalUsoDoSoloEMudancaDeUsoDoSolo: 0.0246; PotencialDeEutrofizacaoFraccaoDeNutrientesQueAtingemOCompartimentoFinalDeAguaDoce: 0.000189; PotencialDeEutrofizacaoFraccaoDeNutrientesQueAtingemOCompartimentoFinalMarinho: 0.0122; EnergiaRecuperada: 0.00739; ConsumoDeAguaDoce: 0.113; UtilizacaoLiquidaDeAguaDoce: 0.113; ResiduosPerigososEliminados: 0.00221; ResiduosNaoPerigososEliminados: 1.83; MassaTotalDeResiduosRadioactivosEliminados: 0.000394; EnergiaElectricaExportada: 1.55; MateriaisParaRecuperacaoDeEnergia: 0.00739; MateriaisParaReciclagem: 0.0253; UnidadeEPD: 1 m²
Type - IFC.REVIGRÉS-Dados gerais-Floor Covering - Nome: REVIGRÉS-OMNISTONE-HEXAGON-60X60-SOFT-IRON; TipoProduto: Prensado a seco: grupo BIa UGL | Grés porcelânico técnico; NumeroDeRegistoDAP: EPD-REV-20240006-CCC1-EN; ReferenciaDAP: -; UrlDOP: -
Classification: C3020 (Uniformat)
Pset_CoveringCommon - TotalThickness: 9.8 mm
IFC.REVIGRÉS-Dados do fabricante-Floor Covering - Type: Floor: REVIGRÉS-OMNISTONE-HEXAGON-60X60-SOFT-IRON
IFC.REVIGRÉS-Dados de desempenho-Floor Covering - Type: Floor: REVIGRÉS-OMNISTONE-HEXAGON-60X60-SOFT-IRON
IFC.REVIGRÉS-Dados de especificação-Floor Covering - Type: Floor: REVIGRÉS-OMNISTONE-HEXAGON-60X60-SOFT-IRON
IFC.REVIGRÉS-Dados geométricos-Floor Covering - Type: Floor: REVIGRÉS-OMNISTONE-HEXAGON-60X60-SOFT-IRON
IFC.REVIGRÉS-Dados de sustentabilidade-Floor Covering - Type: Floor: REVIGRÉS-OMNISTONE-HEXAGON-60X60-SOFT-IRON

# IfcCovering: Floor:REVIGRÉS-OMNISTONE-HEXAGON-60X60-SOFT-JET, Floor:REVIGRÉS-OMNISTONE-HEXAGON-60X60-SOFT-JET:155136
In: Level 1
Type - PredefinedType: CLADDING; Material: REVIGRÉS-OMNISTONE-HEXAGON-60x60-SOFT-JET 9.8 mm
Type - Pset_CoveringCommon - Reference: 332613V221; Material: Grés porcelânico
Type - Pset_ElementShading - Roughness: 304.8 mm
Type - Pset_ManufacturerTypeInformation - Manufacturer: REVIGRÉS
Type - Pset_ProductRequirements - Category: Floors
Type - Pset_QuantityTakeOff - Reference: 332613V221
Type - IFC.REVIGRÉS-Dados do fabricante-Floor Covering - FabricanteURL: https://www.revigres.pt/; ReferenciaModelo: Omnistone; NumeroGlobalDeItemComercial: 332613V221; Acabamento: SOFT; Material: Grés porcelânico; IdentificadorDoOperadorEconomico: 501840856; UrlFabricanteArtigo: https://www.revigres.pt/colecoes/omnistone; PaisOrigem: Portugal
Type - IFC.REVIGRÉS-Dados de desempenho-Floor Covering - Rectilinearidade: ± 0.2% máx.± 0.8 mm; Ortogonalidade: ± 0.2% máx.± 1.5 mm; PlanaridadeDaSuperficie: ± 0.3% máx. ± 1.8 mm; QualidadeDaSuperficie: Cumpre; AbsorcaoDeAgua: < 0.05%; ModuloDeRuptura: > 45 N/mm130; ResistenciaAFlexao: ≥ 3500 N; ResistenciaAAbrasaoProfunda: < 120 mm131; DilatacaoTermicaLinear: ≤ 8,0x10-6 °C-1; ResistenciaAoChoqueTermico: Resiste; DurabilidadeResistenciaAoGeloDegelo: Resiste; ResistenciaAsManchas: Class 5; ResistenciaABaixasConcentracoesDeAcidosEAlcalis: Classe LA; ResistenciaAAltasConcentracoesDeAcidosEAlcalis: Classe HA; LibertacaoDeCadmio: 0; LibertacaoDeChumbo: 0
Type - IFC.REVIGRÉS-Dados de especificação-Floor Covering - VariacaoTonalidade: 3; NivelDeTrafego: 5; EPavimento: Sim; ERevestimento: Sim; EExterno: Sim
Type - IFC.REVIGRÉS-Dados geométricos-Floor Covering - AlturaNominal: 9.8 mm; ComprimentoNominal: 59.2 mm; LarguraNominal: 59.2 mm
Type - IFC.REVIGRÉS-Dados de sustentabilidade-Floor Covering - ItemEParcialmenteReciclado: 0; EnergiaTermicaExportada: 0; ItemENovo: Sim; ItemEReciclado: Não; VidaÚtilEsperada: 50; SubstanciasPerigosas: Não; PotencialDeEsgotamentoAbioticoDosRecursosNaoFosseisMineraisEMetais: 0.000701; PotencialDeAquecimentoGlobalBiogenico: -0.48; CombustiveisFosseisComPotencialDeAquecimentoGlobal: 13.9; PotencialDeAquecimentoGlobalUsoDoSoloEMudancaDeUsoDoSolo: 0.0246; PotencialDeEutrofizacaoFraccaoDeNutrientesQueAtingemOCompartimentoFinalDeAguaDoce: 0.000189; PotencialDeEutrofizacaoFraccaoDeNutrientesQueAtingemOCompartimentoFinalMarinho: 0.0122; EnergiaRecuperada: 0.00739; ConsumoDeAguaDoce: 0.113; UtilizacaoLiquidaDeAguaDoce: 0.113; ResiduosPerigososEliminados: 0.00221; ResiduosNaoPerigososEliminados: 1.83; MassaTotalDeResiduosRadioactivosEliminados: 0.000394; EnergiaElectricaExportada: 1.55; MateriaisParaRecuperacaoDeEnergia: 0.00739; MateriaisParaReciclagem: 0.0253; UnidadeEPD: 1 m²
Type - IFC.REVIGRÉS-Dados gerais-Floor Covering - Nome: REVIGRÉS-OMNISTONE-HEXAGON-60X60-SOFT-JET; TipoProduto: Prensado a seco: grupo BIa UGL | Grés porcelânico técnico; NumeroDeRegistoDAP: EPD-REV-20240006-CCC1-EN; ReferenciaDAP: -; UrlDOP: -
Classification: C3020 (Uniformat)
Pset_CoveringCommon - TotalThickness: 9.8 mm
IFC.REVIGRÉS-Dados do fabricante-Floor Covering - Type: Floor: REVIGRÉS-OMNISTONE-HEXAGON-60X60-SOFT-JET
IFC.REVIGRÉS-Dados de desempenho-Floor Covering - Type: Floor: REVIGRÉS-OMNISTONE-HEXAGON-60X60-SOFT-JET
IFC.REVIGRÉS-Dados de especificação-Floor Covering - Type: Floor: REVIGRÉS-OMNISTONE-HEXAGON-60X60-SOFT-JET
IFC.REVIGRÉS-Dados geométricos-Floor Covering - Type: Floor: REVIGRÉS-OMNISTONE-HEXAGON-60X60-SOFT-JET
IFC.REVIGRÉS-Dados de sustentabilidade-Floor Covering - Type: Floor: REVIGRÉS-OMNISTONE-HEXAGON-60X60-SOFT-JET

# IfcCovering: Floor:REVIGRÉS-OMNISTONE-HEXAGON-60X60-SOFT-PLATINA, Floor:REVIGRÉS-OMNISTONE-HEXAGON-60X60-SOFT-PLATINA:155243
In: Level 1
Type - PredefinedType: CLADDING; Material: REVIGRÉS-OMNISTONE-HEXAGON-60x60-SOFT-PLATINA 9.8 mm
Type - Pset_CoveringCommon - Reference: 332613V231; Material: Grés porcelânico
Type - Pset_ElementShading - Roughness: 304.8 mm
Type - Pset_ManufacturerTypeInformation - Manufacturer: REVIGRÉS
Type - Pset_ProductRequirements - Category: Floors
Type - Pset_QuantityTakeOff - Reference: 332613V231
Type - IFC.REVIGRÉS-Dados do fabricante-Floor Covering - FabricanteURL: https://www.revigres.pt/; ReferenciaModelo: Omnistone; NumeroGlobalDeItemComercial: 332613V231; Acabamento: SOFT; Material: Grés porcelânico; IdentificadorDoOperadorEconomico: 501840856; UrlFabricanteArtigo: https://www.revigres.pt/colecoes/omnistone; PaisOrigem: Portugal
Type - IFC.REVIGRÉS-Dados de desempenho-Floor Covering - Rectilinearidade: ± 0.2% máx.± 0.8 mm; Ortogonalidade: ± 0.2% máx.± 1.5 mm; PlanaridadeDaSuperficie: ± 0.3% máx. ± 1.8 mm; QualidadeDaSuperficie: Cumpre; AbsorcaoDeAgua: < 0.05%; ModuloDeRuptura: > 45 N/mm130; ResistenciaAFlexao: ≥ 3500 N; ResistenciaAAbrasaoProfunda: < 120 mm131; DilatacaoTermicaLinear: ≤ 8,0x10-6 °C-1; ResistenciaAoChoqueTermico: Resiste; DurabilidadeResistenciaAoGeloDegelo: Resiste; ResistenciaAsManchas: Class 5; ResistenciaABaixasConcentracoesDeAcidosEAlcalis: Classe LA; ResistenciaAAltasConcentracoesDeAcidosEAlcalis: Classe HA; LibertacaoDeCadmio: 0; LibertacaoDeChumbo: 0
Type - IFC.REVIGRÉS-Dados de especificação-Floor Covering - VariacaoTonalidade: 3; NivelDeTrafego: 5; EPavimento: Sim; ERevestimento: Sim; EExterno: Sim
Type - IFC.REVIGRÉS-Dados geométricos-Floor Covering - AlturaNominal: 9.8 mm; ComprimentoNominal: 59.2 mm; LarguraNominal: 59.2 mm
Type - IFC.REVIGRÉS-Dados de sustentabilidade-Floor Covering - ItemEParcialmenteReciclado: 0; EnergiaTermicaExportada: 0; ItemENovo: Sim; ItemEReciclado: Não; VidaÚtilEsperada: 50; SubstanciasPerigosas: Não; PotencialDeEsgotamentoAbioticoDosRecursosNaoFosseisMineraisEMetais: 0.000701; PotencialDeAquecimentoGlobalBiogenico: -0.48; CombustiveisFosseisComPotencialDeAquecimentoGlobal: 13.9; PotencialDeAquecimentoGlobalUsoDoSoloEMudancaDeUsoDoSolo: 0.0246; PotencialDeEutrofizacaoFraccaoDeNutrientesQueAtingemOCompartimentoFinalDeAguaDoce: 0.000189; PotencialDeEutrofizacaoFraccaoDeNutrientesQueAtingemOCompartimentoFinalMarinho: 0.0122; EnergiaRecuperada: 0.00739; ConsumoDeAguaDoce: 0.113; UtilizacaoLiquidaDeAguaDoce: 0.113; ResiduosPerigososEliminados: 0.00221; ResiduosNaoPerigososEliminados: 1.83; MassaTotalDeResiduosRadioactivosEliminados: 0.000394; EnergiaElectricaExportada: 1.55; MateriaisParaRecuperacaoDeEnergia: 0.00739; MateriaisParaReciclagem: 0.0253; UnidadeEPD: 1 m²
Type - IFC.REVIGRÉS-Dados gerais-Floor Covering - Nome: REVIGRÉS-OMNISTONE-HEXAGON-60X60-SOFT-PLATINA; TipoProduto: Prensado a seco: grupo BIa UGL | Grés porcelânico técnico; NumeroDeRegistoDAP: EPD-REV-20240006-CCC1-EN; ReferenciaDAP: -; UrlDOP: -
Classification: C3020 (Uniformat)
Pset_CoveringCommon - TotalThickness: 9.8 mm
IFC.REVIGRÉS-Dados do fabricante-Floor Covering - Type: Floor: REVIGRÉS-OMNISTONE-HEXAGON-60X60-SOFT-PLATINA
IFC.REVIGRÉS-Dados de desempenho-Floor Covering - Type: Floor: REVIGRÉS-OMNISTONE-HEXAGON-60X60-SOFT-PLATINA
IFC.REVIGRÉS-Dados de especificação-Floor Covering - Type: Floor: REVIGRÉS-OMNISTONE-HEXAGON-60X60-SOFT-PLATINA
IFC.REVIGRÉS-Dados geométricos-Floor Covering - Type: Floor: REVIGRÉS-OMNISTONE-HEXAGON-60X60-SOFT-PLATINA
IFC.REVIGRÉS-Dados de sustentabilidade-Floor Covering - Type: Floor: REVIGRÉS-OMNISTONE-HEXAGON-60X60-SOFT-PLATINA

# IfcCovering: Floor:REVIGRÉS-OMNISTONE-HEXAGON-60X60-SOFT-ROPE, Floor:REVIGRÉS-OMNISTONE-HEXAGON-60X60-SOFT-ROPE:155365
In: Level 1
Type - PredefinedType: CLADDING; Material: REVIGRÉS-OMNISTONE-HEXAGON-60x60-SOFT-ROPE 9.8 mm
Type - Pset_CoveringCommon - Reference: 332613V241; Material: Grés porcelânico
Type - Pset_ElementShading - Roughness: 304.8 mm
Type - Pset_ManufacturerTypeInformation - Manufacturer: REVIGRÉS
Type - Pset_ProductRequirements - Category: Floors
Type - Pset_QuantityTakeOff - Reference: 332613V241
Type - IFC.REVIGRÉS-Dados do fabricante-Floor Covering - FabricanteURL: https://www.revigres.pt/; ReferenciaModelo: Omnistone; NumeroGlobalDeItemComercial: 332613V241; Acabamento: SOFT; Material: Grés porcelânico; IdentificadorDoOperadorEconomico: 501840856; UrlFabricanteArtigo: https://www.revigres.pt/colecoes/omnistone; PaisOrigem: Portugal
Type - IFC.REVIGRÉS-Dados de desempenho-Floor Covering - Rectilinearidade: ± 0.2% máx.± 0.8 mm; Ortogonalidade: ± 0.2% máx.± 1.5 mm; PlanaridadeDaSuperficie: ± 0.3% máx. ± 1.8 mm; QualidadeDaSuperficie: Cumpre; AbsorcaoDeAgua: < 0.05%; ModuloDeRuptura: > 45 N/mm130; ResistenciaAFlexao: ≥ 3500 N; ResistenciaAAbrasaoProfunda: < 120 mm131; DilatacaoTermicaLinear: ≤ 8,0x10-6 °C-1; ResistenciaAoChoqueTermico: Resiste; DurabilidadeResistenciaAoGeloDegelo: Resiste; ResistenciaAsManchas: Class 5; ResistenciaABaixasConcentracoesDeAcidosEAlcalis: Classe LA; ResistenciaAAltasConcentracoesDeAcidosEAlcalis: Classe HA; LibertacaoDeCadmio: 0; LibertacaoDeChumbo: 0
Type - IFC.REVIGRÉS-Dados de especificação-Floor Covering - VariacaoTonalidade: 3; NivelDeTrafego: 5; EPavimento: Sim; ERevestimento: Sim; EExterno: Sim
Type - IFC.REVIGRÉS-Dados geométricos-Floor Covering - AlturaNominal: 9.8 mm; ComprimentoNominal: 59.2 mm; LarguraNominal: 59.2 mm
Type - IFC.REVIGRÉS-Dados de sustentabilidade-Floor Covering - ItemEParcialmenteReciclado: 0; EnergiaTermicaExportada: 0; ItemENovo: Sim; ItemEReciclado: Não; VidaÚtilEsperada: 50; SubstanciasPerigosas: Não; PotencialDeEsgotamentoAbioticoDosRecursosNaoFosseisMineraisEMetais: 0.000701; PotencialDeAquecimentoGlobalBiogenico: -0.48; CombustiveisFosseisComPotencialDeAquecimentoGlobal: 13.9; PotencialDeAquecimentoGlobalUsoDoSoloEMudancaDeUsoDoSolo: 0.0246; PotencialDeEutrofizacaoFraccaoDeNutrientesQueAtingemOCompartimentoFinalDeAguaDoce: 0.000189; PotencialDeEutrofizacaoFraccaoDeNutrientesQueAtingemOCompartimentoFinalMarinho: 0.0122; EnergiaRecuperada: 0.00739; ConsumoDeAguaDoce: 0.113; UtilizacaoLiquidaDeAguaDoce: 0.113; ResiduosPerigososEliminados: 0.00221; ResiduosNaoPerigososEliminados: 1.83; MassaTotalDeResiduosRadioactivosEliminados: 0.000394; EnergiaElectricaExportada: 1.55; MateriaisParaRecuperacaoDeEnergia: 0.00739; MateriaisParaReciclagem: 0.0253; UnidadeEPD: 1 m²
Type - IFC.REVIGRÉS-Dados gerais-Floor Covering - Nome: REVIGRÉS-OMNISTONE-HEXAGON-60X60-SOFT-ROPE; TipoProduto: Prensado a seco: grupo BIa UGL | Grés porcelânico técnico; NumeroDeRegistoDAP: EPD-REV-20240006-CCC1-EN; ReferenciaDAP: -; UrlDOP: -
Classification: C3020 (Uniformat)
Pset_CoveringCommon - TotalThickness: 9.8 mm
IFC.REVIGRÉS-Dados do fabricante-Floor Covering - Type: Floor: REVIGRÉS-OMNISTONE-HEXAGON-60X60-SOFT-ROPE
IFC.REVIGRÉS-Dados de desempenho-Floor Covering - Type: Floor: REVIGRÉS-OMNISTONE-HEXAGON-60X60-SOFT-ROPE
IFC.REVIGRÉS-Dados de especificação-Floor Covering - Type: Floor: REVIGRÉS-OMNISTONE-HEXAGON-60X60-SOFT-ROPE
IFC.REVIGRÉS-Dados geométricos-Floor Covering - Type: Floor: REVIGRÉS-OMNISTONE-HEXAGON-60X60-SOFT-ROPE
IFC.REVIGRÉS-Dados de sustentabilidade-Floor Covering - Type: Floor: REVIGRÉS-OMNISTONE-HEXAGON-60X60-SOFT-ROPE

# IfcWallStandardCase: Basic Wall:REVIGRÉS-OMNISTONE-HEXAGON-60X60-MATTRECT-BONE, Basic Wall:REVIGRÉS-OMNISTONE-HEXAGON-60X60-MATTRECT-BONE:154491
In: Level 1
Type - PredefinedType: STANDARD; Material: REVIGRÉS-OMNISTONE-HEXAGON-60x60-MATTRECT-BONE 9.8 mm
Type - Pset_ElementShading - Roughness: 304.8 mm
Type - Pset_ManufacturerTypeInformation - Manufacturer: REVIGRÉS
Type - Pset_ProductRequirements - Category: Walls
Type - Pset_QuantityTakeOff - Reference: 332B13V191
Type - Pset_ReinforcementBarPitchOfWall - Reference: 332B13V191
Type - Pset_WallCommon - Reference: 332B13V191; IsExternal: no
Type - IFC.REVIGRÉS-Dados do fabricante-Wall Covering - FabricanteURL: https://www.revigres.pt/; ReferenciaModelo: Omnistone; NumeroGlobalDeItemComercial: 332B13V191; Acabamento: MATT RECT; Material: Grés porcelânico; IdentificadorDoOperadorEconomico: 501840856; UrlFabricanteArtigo: https://www.revigres.pt/colecoes/omnistone; PaisOrigem: Portugal
Type - IFC.REVIGRÉS-Dados de desempenho-Wall Covering - Rectilinearidade: ± 0.2% máx.± 0.8 mm; Ortogonalidade: ± 0.2% máx.± 1.5 mm; PlanaridadeDaSuperficie: ± 0.3% máx. ± 1.8 mm; QualidadeDaSuperficie: Cumpre; AbsorcaoDeAgua: < 0.05%; ModuloDeRuptura: > 45 N/mm130; ResistenciaAFlexao: ≥ 3500 N; ResistenciaAAbrasaoProfunda: < 120 mm131; DilatacaoTermicaLinear: ≤ 8,0x10-6 °C-1; ResistenciaAoChoqueTermico: Resiste; DurabilidadeResistenciaAoGeloDegelo: Resiste; ResistenciaAoEscorregamentoDIN51130: R10; ResistenciaAoEscorregamentoDIN51097: B; ResistenciaAoEscorregamentoENV51097: B; ResistenciaAoEscorregamentoENV12633: Class 2; ResistenciaAoEscorregamentoBS7976: >36; ResistenciaAoEscorregamentoANSIA1371: ≥0,42; ResistenciaAoDeslizamentoENV12633: Class 2; ResistenciaAoDeslizamentoBS7976: >36; ResistenciaAsManchas: Class 5; ResistenciaABaixasConcentracoesDeAcidosEAlcalis: Classe LA; ResistenciaAAltasConcentracoesDeAcidosEAlcalis: Classe HA; LibertacaoDeCadmio: 0; LibertacaoDeChumbo: 0
Type - IFC.REVIGRÉS-Dados de especificação-Wall Covering - VariacaoTonalidade: 3; NivelDeTrafego: 5; EPavimento: Sim; ERevestimento: Sim; EExterno: Sim
Type - IFC.REVIGRÉS-Dados geométricos-Wall Covering - AlturaNominal: 9.8 mm; ComprimentoNominal: 59.2 mm; LarguraNominal: 59.2 mm
Type - IFC.REVIGRÉS-Dados de sustentabilidade-Wall Covering - ItemEParcialmenteReciclado: 0; EnergiaTermicaExportada: 0; ItemENovo: Sim; ItemEReciclado: Não; VidaÚtilEsperada: 50; SubstanciasPerigosas: Não; PotencialDeEsgotamentoAbioticoDosRecursosNaoFosseisMineraisEMetais: 0.000701; PotencialDeAquecimentoGlobalBiogenico: -0.48; CombustiveisFosseisComPotencialDeAquecimentoGlobal: 13.9; PotencialDeAquecimentoGlobalUsoDoSoloEMudancaDeUsoDoSolo: 0.0246; PotencialDeEutrofizacaoFraccaoDeNutrientesQueAtingemOCompartimentoFinalDeAguaDoce: 0.000189; PotencialDeEutrofizacaoFraccaoDeNutrientesQueAtingemOCompartimentoFinalMarinho: 0.0122; PotencialPrivacaoDeAguaConsumoDeAguaPonderado: 4.5; EnergiaRecuperada: 0.00739; ConsumoDeAguaDoce: 0.113; UtilizacaoLiquidaDeAguaDoce: 0.113; ResiduosPerigososEliminados: 0.00221; ResiduosNaoPerigososEliminados: 1.83; MassaTotalDeResiduosRadioactivosEliminados: 0.000394; EnergiaElectricaExportada: 1.55; MateriaisParaRecuperacaoDeEnergia: 0.00739; MateriaisParaReciclagem: 0.0253; UnidadeEPD: 1 m²
Type - IFC.REVIGRÉS-Dados gerais-Wall Covering - Nome: REVIGRÉS-OMNISTONE-HEXAGON-60X60-MATT RECT-BONE; TipoProduto: Prensado a seco: grupo BIa UGL | Grés porcelânico técnico; NumeroDeRegistoDAP: EPD-REV-20240006-CCC1-EN; ReferenciaDAP: -; UrlDOP: -
Classification: C3010 (Uniformat)
Pset_QuantityTakeOff - sets with these values: 2
Pset_WallCommon - ExtendToStructure: no; LoadBearing: no
IFC.REVIGRÉS-Dados do fabricante-Wall Covering - Type: Basic Wall: REVIGRÉS-OMNISTONE-HEXAGON-60X60-MATTRECT-BONE
IFC.REVIGRÉS-Dados de desempenho-Wall Covering - Type: Basic Wall: REVIGRÉS-OMNISTONE-HEXAGON-60X60-MATTRECT-BONE
IFC.REVIGRÉS-Dados de especificação-Wall Covering - Type: Basic Wall: REVIGRÉS-OMNISTONE-HEXAGON-60X60-MATTRECT-BONE
IFC.REVIGRÉS-Dados geométricos-Wall Covering - Type: Basic Wall: REVIGRÉS-OMNISTONE-HEXAGON-60X60-MATTRECT-BONE
IFC.REVIGRÉS-Dados de sustentabilidade-Wall Covering - Type: Basic Wall: REVIGRÉS-OMNISTONE-HEXAGON-60X60-MATTRECT-BONE

# IfcWallStandardCase: Basic Wall:REVIGRÉS-OMNISTONE-HEXAGON-60X60-MATTRECT-ICE, Basic Wall:REVIGRÉS-OMNISTONE-HEXAGON-60X60-MATTRECT-ICE:154654
In: Level 1
Type - PredefinedType: STANDARD; Material: REVIGRÉS-OMNISTONE-HEXAGON-60x60-MATTRECT-ICE 9.8 mm
Type - Pset_ElementShading - Roughness: 304.8 mm
Type - Pset_ManufacturerTypeInformation - Manufacturer: REVIGRÉS
Type - Pset_ProductRequirements - Category: Walls
Type - Pset_QuantityTakeOff - Reference: 332B13V201
Type - Pset_ReinforcementBarPitchOfWall - Reference: 332B13V201
Type - Pset_WallCommon - IsExternal: no; Reference: 332B13V201
Type - IFC.REVIGRÉS-Dados do fabricante-Wall Covering - FabricanteURL: https://www.revigres.pt/; ReferenciaModelo: Omnistone; NumeroGlobalDeItemComercial: 332B13V201; Acabamento: MATT RECT; Material: Grés porcelânico; IdentificadorDoOperadorEconomico: 501840856; UrlFabricanteArtigo: https://www.revigres.pt/colecoes/omnistone; PaisOrigem: Portugal
Type - IFC.REVIGRÉS-Dados de desempenho-Wall Covering - Rectilinearidade: ± 0.2% máx.± 0.8 mm; Ortogonalidade: ± 0.2% máx.± 1.5 mm; PlanaridadeDaSuperficie: ± 0.3% máx. ± 1.8 mm; QualidadeDaSuperficie: Cumpre; AbsorcaoDeAgua: < 0.05%; ModuloDeRuptura: > 45 N/mm130; ResistenciaAFlexao: ≥ 3500 N; ResistenciaAAbrasaoProfunda: < 120 mm131; DilatacaoTermicaLinear: ≤ 8,0x10-6 °C-1; ResistenciaAoChoqueTermico: Resiste; DurabilidadeResistenciaAoGeloDegelo: Resiste; ResistenciaAoEscorregamentoDIN51130: R10; ResistenciaAoEscorregamentoDIN51097: B; ResistenciaAoEscorregamentoENV51097: B; ResistenciaAoEscorregamentoENV12633: Class 2; ResistenciaAoEscorregamentoBS7976: >36; ResistenciaAoEscorregamentoANSIA1371: ≥0,42; ResistenciaAoDeslizamentoENV12633: Class 2; ResistenciaAoDeslizamentoBS7976: >36; ResistenciaAsManchas: Class 5; ResistenciaABaixasConcentracoesDeAcidosEAlcalis: Classe LA; ResistenciaAAltasConcentracoesDeAcidosEAlcalis: Classe HA; LibertacaoDeCadmio: 0; LibertacaoDeChumbo: 0
Type - IFC.REVIGRÉS-Dados de especificação-Wall Covering - VariacaoTonalidade: 3; NivelDeTrafego: 5; EPavimento: Sim; ERevestimento: Sim; EExterno: Sim
Type - IFC.REVIGRÉS-Dados geométricos-Wall Covering - AlturaNominal: 9.8 mm; ComprimentoNominal: 59.2 mm; LarguraNominal: 59.2 mm
Type - IFC.REVIGRÉS-Dados de sustentabilidade-Wall Covering - ItemEParcialmenteReciclado: 0; EnergiaTermicaExportada: 0; PotencialPrivacaoDeAguaConsumoDeAguaPonderado: 4.5; ItemENovo: Sim; ItemEReciclado: Não; VidaÚtilEsperada: 50; SubstanciasPerigosas: Não; PotencialDeEsgotamentoAbioticoDosRecursosNaoFosseisMineraisEMetais: 0.000701; PotencialDeAquecimentoGlobalBiogenico: -0.48; CombustiveisFosseisComPotencialDeAquecimentoGlobal: 13.9; PotencialDeAquecimentoGlobalUsoDoSoloEMudancaDeUsoDoSolo: 0.0246; PotencialDeEutrofizacaoFraccaoDeNutrientesQueAtingemOCompartimentoFinalDeAguaDoce: 0.000189; PotencialDeEutrofizacaoFraccaoDeNutrientesQueAtingemOCompartimentoFinalMarinho: 0.0122; EnergiaRecuperada: 0.00739; ConsumoDeAguaDoce: 0.113; UtilizacaoLiquidaDeAguaDoce: 0.113; ResiduosPerigososEliminados: 0.00221; ResiduosNaoPerigososEliminados: 1.83; MassaTotalDeResiduosRadioactivosEliminados: 0.000394; EnergiaElectricaExportada: 1.55; MateriaisParaRecuperacaoDeEnergia: 0.00739; MateriaisParaReciclagem: 0.0253; UnidadeEPD: 1 m²
Type - IFC.REVIGRÉS-Dados gerais-Wall Covering - Nome: REVIGRÉS-OMNISTONE-HEXAGON-60X60-MATT RECT-ICE; TipoProduto: Prensado a seco: grupo BIa UGL | Grés porcelânico técnico; NumeroDeRegistoDAP: EPD-REV-20240006-CCC1-EN; ReferenciaDAP: -; UrlDOP: -
Classification: C3010 (Uniformat)
Pset_QuantityTakeOff - sets with these values: 2
Pset_WallCommon - ExtendToStructure: no; LoadBearing: no
IFC.REVIGRÉS-Dados do fabricante-Wall Covering - Type: Basic Wall: REVIGRÉS-OMNISTONE-HEXAGON-60X60-MATTRECT-ICE
IFC.REVIGRÉS-Dados de desempenho-Wall Covering - Type: Basic Wall: REVIGRÉS-OMNISTONE-HEXAGON-60X60-MATTRECT-ICE
IFC.REVIGRÉS-Dados de especificação-Wall Covering - Type: Basic Wall: REVIGRÉS-OMNISTONE-HEXAGON-60X60-MATTRECT-ICE
IFC.REVIGRÉS-Dados geométricos-Wall Covering - Type: Basic Wall: REVIGRÉS-OMNISTONE-HEXAGON-60X60-MATTRECT-ICE
IFC.REVIGRÉS-Dados de sustentabilidade-Wall Covering - Type: Basic Wall: REVIGRÉS-OMNISTONE-HEXAGON-60X60-MATTRECT-ICE

# IfcWallStandardCase: Basic Wall:REVIGRÉS-OMNISTONE-HEXAGON-60X60-MATTRECT-IRON, Basic Wall:REVIGRÉS-OMNISTONE-HEXAGON-60X60-MATTRECT-IRON:155033
In: Level 1
Type - PredefinedType: STANDARD; Material: REVIGRÉS-OMNISTONE-HEXAGON-60x60-MATTRECT-IRON 9.8 mm
Type - Pset_ElementShading - Roughness: 304.8 mm
Type - Pset_ManufacturerTypeInformation - Manufacturer: REVIGRÉS
Type - Pset_ProductRequirements - Category: Walls
Type - Pset_QuantityTakeOff - Reference: 332B13V211
Type - Pset_ReinforcementBarPitchOfWall - Reference: 332B13V211
Type - Pset_WallCommon - IsExternal: no; Reference: 332B13V211
Type - IFC.REVIGRÉS-Dados do fabricante-Wall Covering - FabricanteURL: https://www.revigres.pt/; ReferenciaModelo: Omnistone; NumeroGlobalDeItemComercial: 332B13V211; Acabamento: MATT RECT; Material: Grés porcelânico; IdentificadorDoOperadorEconomico: 501840856; UrlFabricanteArtigo: https://www.revigres.pt/colecoes/omnistone; PaisOrigem: Portugal
Type - IFC.REVIGRÉS-Dados de desempenho-Wall Covering - Rectilinearidade: ± 0.2% máx.± 0.8 mm; Ortogonalidade: ± 0.2% máx.± 1.5 mm; PlanaridadeDaSuperficie: ± 0.3% máx. ± 1.8 mm; QualidadeDaSuperficie: Cumpre; AbsorcaoDeAgua: < 0.05%; ModuloDeRuptura: > 45 N/mm130; ResistenciaAFlexao: ≥ 3500 N; ResistenciaAAbrasaoProfunda: < 120 mm131; DilatacaoTermicaLinear: ≤ 8,0x10-6 °C-1; ResistenciaAoChoqueTermico: Resiste; DurabilidadeResistenciaAoGeloDegelo: Resiste; ResistenciaAoEscorregamentoDIN51130: R10; ResistenciaAoEscorregamentoDIN51097: B; ResistenciaAoEscorregamentoENV51097: B; ResistenciaAoEscorregamentoENV12633: Class 2; ResistenciaAoEscorregamentoBS7976: >36; ResistenciaAoEscorregamentoANSIA1371: ≥0,42; ResistenciaAoDeslizamentoENV12633: Class 2; ResistenciaAoDeslizamentoBS7976: >36; ResistenciaAsManchas: Class 5; ResistenciaABaixasConcentracoesDeAcidosEAlcalis: Classe LA; ResistenciaAAltasConcentracoesDeAcidosEAlcalis: Classe HA; LibertacaoDeCadmio: 0; LibertacaoDeChumbo: 0
Type - IFC.REVIGRÉS-Dados de especificação-Wall Covering - VariacaoTonalidade: 3; NivelDeTrafego: 5; EPavimento: Sim; ERevestimento: Sim; EExterno: Sim
Type - IFC.REVIGRÉS-Dados geométricos-Wall Covering - AlturaNominal: 9.8 mm; ComprimentoNominal: 59.2 mm; LarguraNominal: 59.2 mm
Type - IFC.REVIGRÉS-Dados de sustentabilidade-Wall Covering - EnergiaTermicaExportada: 0; PotencialPrivacaoDeAguaConsumoDeAguaPonderado: 4.5; ItemENovo: Sim; ItemEParcialmenteReciclado: 0.14; ItemEReciclado: Sim; VidaÚtilEsperada: 50; SubstanciasPerigosas: Não; PotencialDeEsgotamentoAbioticoDosRecursosNaoFosseisMineraisEMetais: 0.000701; PotencialDeAquecimentoGlobalBiogenico: -0.48; CombustiveisFosseisComPotencialDeAquecimentoGlobal: 13.9; PotencialDeAquecimentoGlobalUsoDoSoloEMudancaDeUsoDoSolo: 0.0246; PotencialDeEutrofizacaoFraccaoDeNutrientesQueAtingemOCompartimentoFinalDeAguaDoce: 0.000189; PotencialDeEutrofizacaoFraccaoDeNutrientesQueAtingemOCompartimentoFinalMarinho: 0.0122; EnergiaRecuperada: 0.00739; ConsumoDeAguaDoce: 0.113; UtilizacaoLiquidaDeAguaDoce: 0.113; ResiduosPerigososEliminados: 0.00221; ResiduosNaoPerigososEliminados: 1.83; MassaTotalDeResiduosRadioactivosEliminados: 0.000394; EnergiaElectricaExportada: 1.55; MateriaisParaRecuperacaoDeEnergia: 0.00739; MateriaisParaReciclagem: 0.0253; UnidadeEPD: 1 m²
Type - IFC.REVIGRÉS-Dados gerais-Wall Covering - Nome: REVIGRÉS-OMNISTONE-HEXAGON-60X60-MATT RECT-IRON; TipoProduto: Prensado a seco: grupo BIa UGL | Grés porcelânico técnico; NumeroDeRegistoDAP: EPD-REV-20240006-CCC1-EN; ReferenciaDAP: -; UrlDOP: -
Classification: C3010 (Uniformat)
Pset_QuantityTakeOff - sets with these values: 2
Pset_WallCommon - ExtendToStructure: no; LoadBearing: no
IFC.REVIGRÉS-Dados do fabricante-Wall Covering - Type: Basic Wall: REVIGRÉS-OMNISTONE-HEXAGON-60X60-MATTRECT-IRON
IFC.REVIGRÉS-Dados de desempenho-Wall Covering - Type: Basic Wall: REVIGRÉS-OMNISTONE-HEXAGON-60X60-MATTRECT-IRON
